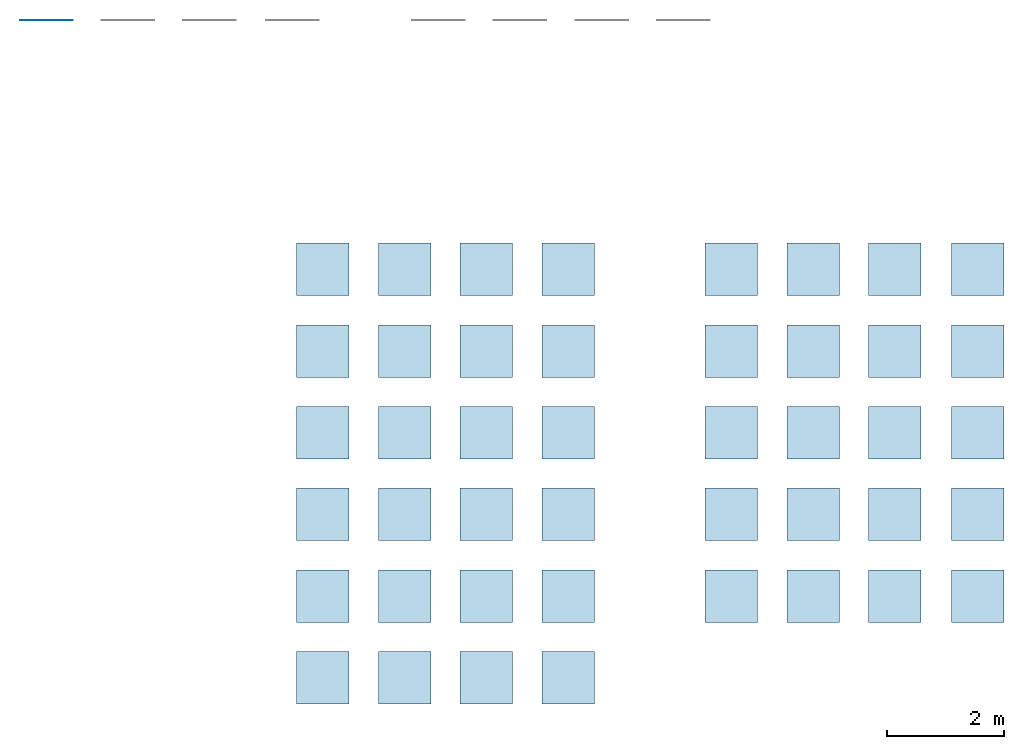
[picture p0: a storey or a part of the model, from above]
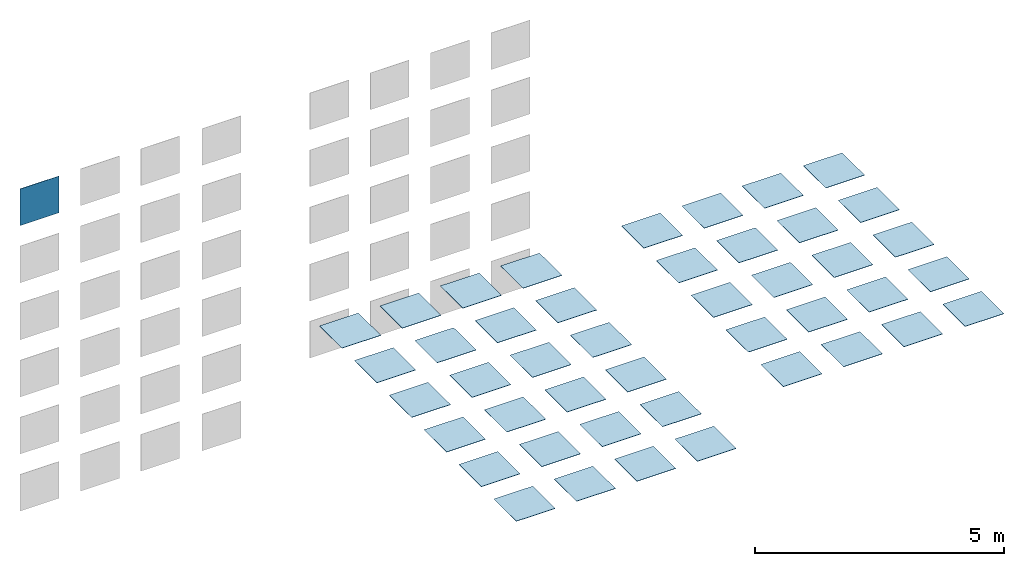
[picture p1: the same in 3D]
Properties of the parts of a building model (IFC2X3)

# File
Description: ViewDefinition [CoordinationView_V2.0]
File name: Número de proyecto
Time: 2017-10-19T10:44:05
Written by: The EXPRESS Data Manager Version 5.02.0100.07 : 28 Aug 2013
Made in: 20160225_1515(x64) - Exporter 17.0.416.0 - Alternate UI 17.12.14.0
Comment: STEP Physical File produced by: The EXPRESS Data Manager Version 5.02.0100.07 : 28 Aug 2013 * Module: EDMstepFileFactory/EDMstandAlone * Creation date: Thu Oct 19 10:44:05 2017 * Host: REVIT * Database: C:\Users\corte\AppData\Local\Temp\{5CBB84B9-D3AB-42C1-A525-BB3D4FEFA5DE}\ifc * Database version: 5507 * Database creation date: Thu Oct 19 10:44:02 2017 * Schema: IFC2X3 * Model: DataRepository.ifc * Model creation date: Thu Oct 19 10:44:02 2017 * Header model: DataRepository.ifc_HeaderModel * Header model creation date: Thu Oct 19 10:44:02 2017 * EDMuser: sdai-user * EDMgroup: sdai-group * License ID and type: 5605 : Permanent license. Expiry date: * EDMstepFileFactory options: 020000

# IfcProject, Número de proyecto
LongName: Nombre de proyecto; Phase: Estado de proyecto

# IfcSite, Default
RefLatitude: 40, 25, 0, 86975; RefLongitude: -3, -42, -1, -243858; RefElevation: 0 m

# IfcBuilding
Pset_BuildingCommon - NumberOfStoreys: 1

# IfcBuildingStorey, FARNESE FLOOR TILES
LongName: FARNESE FLOOR TILES; Elevation: 0 m

# IfcSlab: Suelo:VIVES AMALFI AZUL 30X30, Suelo:VIVES AMALFI AZUL 30X30:194230
In: FARNESE FLOOR TILES
PredefinedType: FLOOR; Material: VIVES AMALFI AZUL 30x30 0.0082 m
Pset_SlabCommon - IsExternal: no; LoadBearing: yes; PitchAngle: 0 deg; Reference: VIVES AMALFI AZUL 30X30; ThermalTransmittance: 182.927 kg/K/s3
Pset_ManufacturerTypeInformation - Manufacturer: VIVES Azulejos y Gres S.A.

# IfcSlab: Suelo:VIVES AMALFI BEIGE 30x30, Suelo:VIVES AMALFI BEIGE 30x30:194246
In: FARNESE FLOOR TILES
PredefinedType: FLOOR; Material: VIVES AMALFI BEIGE 30x30 0.0082 m
Pset_SlabCommon - IsExternal: no; LoadBearing: yes; PitchAngle: 0 deg; Reference: VIVES AMALFI BEIGE 30x30; ThermalTransmittance: 182.927 kg/K/s3
Pset_ManufacturerTypeInformation - Manufacturer: VIVES Azulejos y Gres S.A.

# IfcSlab: Suelo:VIVES AMALFI CEMENTO 30x30, Suelo:VIVES AMALFI CEMENTO 30x30:193908
In: FARNESE FLOOR TILES
PredefinedType: FLOOR; Material: VIVES AMALFI CEMENTO 30x30 0.0082 m
Pset_SlabCommon - IsExternal: no; LoadBearing: yes; PitchAngle: 0 deg; Reference: VIVES AMALFI CEMENTO 30x30; ThermalTransmittance: 182.927 kg/K/s3
Pset_ManufacturerTypeInformation - Manufacturer: VIVES Azulejos y Gres S.A.

# IfcSlab: Suelo:VIVES AMALFI CREMA 30x30, Suelo:VIVES AMALFI CREMA 30x30:193916
In: FARNESE FLOOR TILES
PredefinedType: FLOOR; Material: VIVES AMALFI CREMA 30x30 0.0082 m
Pset_SlabCommon - IsExternal: no; LoadBearing: yes; PitchAngle: 0 deg; Reference: VIVES AMALFI CREMA 30x30; ThermalTransmittance: 182.927 kg/K/s3
Pset_ManufacturerTypeInformation - Manufacturer: VIVES Azulejos y Gres S.A.

# IfcSlab: Suelo:VIVES AMALFI GRAFITO 30x30, Suelo:VIVES AMALFI GRAFITO 30x30:193924
In: FARNESE FLOOR TILES
PredefinedType: FLOOR; Material: VIVES AMALFI GRAFITO 30x30 0.0082 m
Pset_SlabCommon - IsExternal: no; LoadBearing: yes; PitchAngle: 0 deg; Reference: VIVES AMALFI GRAFITO 30x30; ThermalTransmittance: 182.927 kg/K/s3
Pset_ManufacturerTypeInformation - Manufacturer: VIVES Azulejos y Gres S.A.

# IfcSlab: Suelo:VIVES AMALFI HUMO 30X30, Suelo:VIVES AMALFI HUMO 30X30:193900
In: FARNESE FLOOR TILES
PredefinedType: FLOOR; Material: VIVES AMALFI HUMO 30x30 0.0082 m
Pset_SlabCommon - IsExternal: no; LoadBearing: yes; PitchAngle: 0 deg; Reference: VIVES AMALFI HUMO 30X30; ThermalTransmittance: 182.927 kg/K/s3
Pset_ManufacturerTypeInformation - Manufacturer: VIVES Azulejos y Gres S.A.

# IfcSlab: Suelo:VIVES AMALFI MAR 30x30, Suelo:VIVES AMALFI MAR 30x30:194238
In: FARNESE FLOOR TILES
PredefinedType: FLOOR; Material: VIVES AMALFI MAR 30x30 0.0082 m
Pset_SlabCommon - IsExternal: no; LoadBearing: yes; PitchAngle: 0 deg; Reference: VIVES AMALFI MAR 30x30; ThermalTransmittance: 182.927 kg/K/s3
Pset_ManufacturerTypeInformation - Manufacturer: VIVES Azulejos y Gres S.A.

# IfcSlab: Suelo:VIVES AMALFI ROSA 30x30, Suelo:VIVES AMALFI ROSA 30x30:194254
In: FARNESE FLOOR TILES
PredefinedType: FLOOR; Material: VIVES AMALFI ROSA 30x30 0.0082 m
Pset_SlabCommon - IsExternal: no; LoadBearing: yes; PitchAngle: 0 deg; Reference: VIVES AMALFI ROSA 30x30; ThermalTransmittance: 182.927 kg/K/s3
Pset_ManufacturerTypeInformation - Manufacturer: VIVES Azulejos y Gres S.A.

# IfcSlab: Suelo:VIVES AMALFI-R AZUL 29.3X29.3, Suelo:VIVES AMALFI-R AZUL 29.3X29.3:196299
In: FARNESE FLOOR TILES
PredefinedType: FLOOR; Material: VIVES AMALFI-R AZUL 29.3x29.3 0.0082 m
Pset_SlabCommon - IsExternal: no; LoadBearing: yes; PitchAngle: 0 deg; Reference: VIVES AMALFI-R AZUL 29.3X29.3; ThermalTransmittance: 182.927 kg/K/s3
Pset_ManufacturerTypeInformation - Manufacturer: VIVES Azulejos y Gres S.A.

# IfcSlab: Suelo:VIVES AMALFI-R BEIGE 29.3X29.3 2, Suelo:VIVES AMALFI-R BEIGE 29.3X29.3 2:196315
In: FARNESE FLOOR TILES
PredefinedType: FLOOR; Material: VIVES AMALFI-R BEIGE 29.3x29.3 0.0082 m
Pset_SlabCommon - IsExternal: no; LoadBearing: yes; PitchAngle: 0 deg; Reference: VIVES AMALFI-R BEIGE 29.3X29.3 2; ThermalTransmittance: 182.927 kg/K/s3
Pset_ManufacturerTypeInformation - Manufacturer: VIVES Azulejos y Gres S.A.

# IfcSlab: Suelo:VIVES AMALFI-R CEMENTO 29.3X29.3, Suelo:VIVES AMALFI-R CEMENTO 29.3X29.3:196037
In: FARNESE FLOOR TILES
PredefinedType: FLOOR; Material: VIVES AMALFI-R CEMENTO 29.3x29.3 0.0082 m
Pset_SlabCommon - IsExternal: no; LoadBearing: yes; PitchAngle: 0 deg; Reference: VIVES AMALFI-R CEMENTO 29.3X29.3; ThermalTransmittance: 182.927 kg/K/s3
Pset_ManufacturerTypeInformation - Manufacturer: VIVES Azulejos y Gres S.A.

# IfcSlab: Suelo:VIVES AMALFI-R CREMA 29.3X29.3, Suelo:VIVES AMALFI-R CREMA 29.3X29.3:196045
In: FARNESE FLOOR TILES
PredefinedType: FLOOR; Material: VIVES AMALFI-R CREMA 29.3x29.3 0.0082 m
Pset_SlabCommon - IsExternal: no; LoadBearing: yes; PitchAngle: 0 deg; Reference: VIVES AMALFI-R CREMA 29.3X29.3; ThermalTransmittance: 182.927 kg/K/s3
Pset_ManufacturerTypeInformation - Manufacturer: VIVES Azulejos y Gres S.A.

# IfcSlab: Suelo:VIVES AMALFI-R GRAFITO 29.3X29.3, Suelo:VIVES AMALFI-R GRAFITO 29.3X29.3:196053
In: FARNESE FLOOR TILES
PredefinedType: FLOOR; Material: VIVES AMALFI-R GRAFITO 29.3x29.3 0.0082 m
Pset_SlabCommon - IsExternal: no; LoadBearing: yes; PitchAngle: 0 deg; Reference: VIVES AMALFI-R GRAFITO 29.3X29.3; ThermalTransmittance: 182.927 kg/K/s3
Pset_ManufacturerTypeInformation - Manufacturer: VIVES Azulejos y Gres S.A.

# IfcSlab: Suelo:VIVES AMALFI-R HUMO 29.3X29.3, Suelo:VIVES AMALFI-R HUMO 29.3X29.3:196029
In: FARNESE FLOOR TILES
PredefinedType: FLOOR; Material: VIVES AMALFI-R HUMO 29.3x29.3 0.0082 m
Pset_SlabCommon - IsExternal: no; LoadBearing: yes; PitchAngle: 0 deg; Reference: VIVES AMALFI-R HUMO 29.3X29.3; ThermalTransmittance: 182.927 kg/K/s3
Pset_ManufacturerTypeInformation - Manufacturer: VIVES Azulejos y Gres S.A.

# IfcSlab: Suelo:VIVES AMALFI-R MAR 29.3X29.3, Suelo:VIVES AMALFI-R MAR 29.3X29.3:196307
In: FARNESE FLOOR TILES
PredefinedType: FLOOR; Material: VIVES AMALFI-R MAR 29.3x29.3 0.0082 m
Pset_SlabCommon - IsExternal: no; LoadBearing: yes; PitchAngle: 0 deg; Reference: VIVES AMALFI-R MAR 29.3X29.3; ThermalTransmittance: 182.927 kg/K/s3
Pset_ManufacturerTypeInformation - Manufacturer: VIVES Azulejos y Gres S.A.

# IfcSlab: Suelo:VIVES AMALFI-R ROSA 29.3X29.3, Suelo:VIVES AMALFI-R ROSA 29.3X29.3:196323
In: FARNESE FLOOR TILES
PredefinedType: FLOOR; Material: VIVES AMALFI-R ROSA 29.3x29.3 0.0082 m
Pset_SlabCommon - IsExternal: no; LoadBearing: yes; PitchAngle: 0 deg; Reference: VIVES AMALFI-R ROSA 29.3X29.3; ThermalTransmittance: 182.927 kg/K/s3
Pset_ManufacturerTypeInformation - Manufacturer: VIVES Azulejos y Gres S.A.

# IfcSlab: Suelo:VIVES APULIA-R CREMA 29.3X29.3, Suelo:VIVES APULIA-R CREMA 29.3X29.3:196544
In: FARNESE FLOOR TILES
PredefinedType: FLOOR; Material: VIVES APULIA-R CREMA 29.3x29.3 0.0082 m
Pset_SlabCommon - IsExternal: no; LoadBearing: yes; PitchAngle: 0 deg; Reference: VIVES APULIA-R CREMA 29.3X29.3; ThermalTransmittance: 182.927 kg/K/s3
Pset_ManufacturerTypeInformation - Manufacturer: VIVES Azulejos y Gres S.A.

# IfcSlab: Suelo:VIVES APULIA-R HUMO 29.3X29.3, Suelo:VIVES APULIA-R HUMO 29.3X29.3:196552
In: FARNESE FLOOR TILES
PredefinedType: FLOOR; Material: VIVES APULIA-R HUMO 29.3x29.3 0.0082 m
Pset_SlabCommon - IsExternal: no; LoadBearing: yes; PitchAngle: 0 deg; Reference: VIVES APULIA-R HUMO 29.3X29.3; ThermalTransmittance: 182.927 kg/K/s3
Pset_ManufacturerTypeInformation - Manufacturer: VIVES Azulejos y Gres S.A.

# IfcSlab: Suelo:VIVES APULIA-R MULTICOLOR 29.3X29.3, Suelo:VIVES APULIA-R MULTICOLOR 29.3X29.3:196536
In: FARNESE FLOOR TILES
PredefinedType: FLOOR; Material: VIVES APULIA-R MULTICOLOR 29.3x29.3 0.0082 m
Pset_SlabCommon - IsExternal: no; LoadBearing: yes; PitchAngle: 0 deg; Reference: VIVES APULIA-R MULTICOLOR 29.3X29.3; ThermalTransmittance: 182.927 kg/K/s3
Pset_ManufacturerTypeInformation - Manufacturer: VIVES Azulejos y Gres S.A.

# IfcSlab: Suelo:VIVES AVENTINO-R CREMA 29.3X29.3, Suelo:VIVES AVENTINO-R CREMA 29.3X29.3:196757
In: FARNESE FLOOR TILES
PredefinedType: FLOOR; Material: VIVES AVENTINO-R CREMA 29.3x29.3 0.0082 m
Pset_SlabCommon - IsExternal: no; LoadBearing: yes; PitchAngle: 0 deg; Reference: VIVES AVENTINO-R CREMA 29.3X29.3; ThermalTransmittance: 182.927 kg/K/s3
Pset_ManufacturerTypeInformation - Manufacturer: VIVES Azulejos y Gres S.A.

# IfcSlab: Suelo:VIVES AVENTINO-R HUMO 29.3X29.3, Suelo:VIVES AVENTINO-R HUMO 29.3X29.3:196765
In: FARNESE FLOOR TILES
PredefinedType: FLOOR; Material: VIVES AVENTINO-R HUMO 29.3x29.3 0.0082 m
Pset_SlabCommon - IsExternal: no; LoadBearing: yes; PitchAngle: 0 deg; Reference: VIVES AVENTINO-R HUMO 29.3X29.3; ThermalTransmittance: 182.927 kg/K/s3
Pset_ManufacturerTypeInformation - Manufacturer: VIVES Azulejos y Gres S.A.

# IfcSlab: Suelo:VIVES CAVOUR AZUL 30x30, Suelo:VIVES CAVOUR AZUL 30x30:195039
In: FARNESE FLOOR TILES
PredefinedType: FLOOR; Material: VIVES CAVOUR AZUL 30x30 0.0082 m
Pset_SlabCommon - IsExternal: no; LoadBearing: yes; PitchAngle: 0 deg; Reference: VIVES CAVOUR AZUL 30x30; ThermalTransmittance: 182.927 kg/K/s3
Pset_ManufacturerTypeInformation - Manufacturer: VIVES Azulejos y Gres S.A.

# IfcSlab: Suelo:VIVES CAVOUR CEMENTO 30x30, Suelo:VIVES CAVOUR CEMENTO 30x30:195031
In: FARNESE FLOOR TILES
PredefinedType: FLOOR; Material: VIVES CAVOUR CEMENTO 30x30 0.0082 m
Pset_SlabCommon - IsExternal: no; LoadBearing: yes; PitchAngle: 0 deg; Reference: VIVES CAVOUR CEMENTO 30x30; ThermalTransmittance: 182.927 kg/K/s3
Pset_ManufacturerTypeInformation - Manufacturer: VIVES Azulejos y Gres S.A.

# IfcSlab: Suelo:VIVES FARNESE CEMENTO 30x30, Suelo:VIVES FARNESE CEMENTO 30x30:193648
In: FARNESE FLOOR TILES
PredefinedType: FLOOR; Material: VIVES FARNESE CEMENTO 30x30 0.0082 m
Pset_SlabCommon - IsExternal: no; LoadBearing: yes; PitchAngle: 0 deg; Reference: VIVES FARNESE CEMENTO 30x30; ThermalTransmittance: 182.927 kg/K/s3
Pset_ManufacturerTypeInformation - Manufacturer: VIVES Azulejos y Gres S.A.

# IfcSlab: Suelo:VIVES FARNESE CREMA 30x30 2, Suelo:VIVES FARNESE CREMA 30x30 2:193729
In: FARNESE FLOOR TILES
PredefinedType: FLOOR; Material: VIVES FARNESE CREMA 30x30 0.0082 m
Pset_SlabCommon - IsExternal: no; LoadBearing: yes; PitchAngle: 0 deg; Reference: VIVES FARNESE CREMA 30x30 2; ThermalTransmittance: 182.927 kg/K/s3
Pset_ManufacturerTypeInformation - Manufacturer: VIVES Azulejos y Gres S.A.

# IfcSlab: Suelo:VIVES FARNESE GRAFITO 30x30, Suelo:VIVES FARNESE GRAFITO 30x30:193795
In: FARNESE FLOOR TILES
PredefinedType: FLOOR; Material: VIVES FARNESE GRAFITO 30x30 0.0082 m
Pset_SlabCommon - IsExternal: no; LoadBearing: yes; PitchAngle: 0 deg; Reference: VIVES FARNESE GRAFITO 30x30; ThermalTransmittance: 182.927 kg/K/s3
Pset_ManufacturerTypeInformation - Manufacturer: VIVES Azulejos y Gres S.A.

# IfcSlab: Suelo:VIVES FARNESE HUMO 30x30, Suelo:VIVES FARNESE HUMO 30x30:189750
In: FARNESE FLOOR TILES
PredefinedType: FLOOR; Material: VIVES FARNESE HUMO 30x30 0.0082 m
Pset_SlabCommon - Reference: VIVES FARNESE HUMO 30x30; IsExternal: no; LoadBearing: yes; ThermalTransmittance: 182.927 kg/K/s3; PitchAngle: 0 deg
Pset_ManufacturerTypeInformation - Manufacturer: VIVES Azulejos y Gres S.A.

# IfcSlab: Suelo:VIVES FARNESE-R CEMENTO 29.3X29.3, Suelo:VIVES FARNESE-R CEMENTO 29.3X29.3:195831
In: FARNESE FLOOR TILES
PredefinedType: FLOOR; Material: VIVES FARNESE-R CEMENTO 29.3x29.3 0.0082 m
Pset_SlabCommon - IsExternal: no; LoadBearing: yes; PitchAngle: 0 deg; Reference: VIVES FARNESE-R CEMENTO 29.3X29.3; ThermalTransmittance: 182.927 kg/K/s3
Pset_ManufacturerTypeInformation - Manufacturer: VIVES Azulejos y Gres S.A.

# IfcSlab: Suelo:VIVES FARNESE-R CREMA 29.3X29.3, Suelo:VIVES FARNESE-R CREMA 29.3X29.3:195897
In: FARNESE FLOOR TILES
PredefinedType: FLOOR; Material: VIVES FARNESE-R CREMA 29.3x29.3 0.0082 m
Pset_SlabCommon - IsExternal: no; LoadBearing: yes; PitchAngle: 0 deg; Reference: VIVES FARNESE-R CREMA 29.3X29.3; ThermalTransmittance: 182.927 kg/K/s3
Pset_ManufacturerTypeInformation - Manufacturer: VIVES Azulejos y Gres S.A.

# IfcSlab: Suelo:VIVES FARNESE-R GRAFITO 29.3X29.3, Suelo:VIVES FARNESE-R GRAFITO 29.3X29.3:195961
In: FARNESE FLOOR TILES
PredefinedType: FLOOR; Material: VIVES FARNESE-R GRAFITO 29.3x29.3 0.0082 m
Pset_SlabCommon - IsExternal: no; LoadBearing: yes; PitchAngle: 0 deg; Reference: VIVES FARNESE-R GRAFITO 29.3X29.3; ThermalTransmittance: 182.927 kg/K/s3
Pset_ManufacturerTypeInformation - Manufacturer: VIVES Azulejos y Gres S.A.

# IfcSlab: Suelo:VIVES FARNESE-R HUMO 29.3X29.3, Suelo:VIVES FARNESE-R HUMO 29.3X29.3:195707
In: FARNESE FLOOR TILES
PredefinedType: FLOOR; Material: VIVES FARNESE-R HUMO 29.3x29.3 0.0082 m
Pset_SlabCommon - IsExternal: no; LoadBearing: yes; PitchAngle: 0 deg; Reference: VIVES FARNESE-R HUMO 29.3X29.3; ThermalTransmittance: 182.927 kg/K/s3
Pset_ManufacturerTypeInformation - Manufacturer: VIVES Azulejos y Gres S.A.

# IfcSlab: Suelo:VIVES GADNER CEMENTO 30x30, Suelo:VIVES GADNER CEMENTO 30x30:195055
In: FARNESE FLOOR TILES
PredefinedType: FLOOR; Material: VIVES GADNER CEMENTO 30x30 0.0082 m
Pset_SlabCommon - IsExternal: no; LoadBearing: yes; PitchAngle: 0 deg; Reference: VIVES GADNER CEMENTO 30x30; ThermalTransmittance: 182.927 kg/K/s3
Pset_ManufacturerTypeInformation - Manufacturer: VIVES Azulejos y Gres S.A.

# IfcSlab: Suelo:VIVES GADNER CREMA 30x30, Suelo:VIVES GADNER CREMA 30x30:195047
In: FARNESE FLOOR TILES
PredefinedType: FLOOR; Material: VIVES GADNER CREMA 30x30 0.0082 m
Pset_SlabCommon - IsExternal: no; LoadBearing: yes; PitchAngle: 0 deg; Reference: VIVES GADNER CREMA 30x30; ThermalTransmittance: 182.927 kg/K/s3
Pset_ManufacturerTypeInformation - Manufacturer: VIVES Azulejos y Gres S.A.

# IfcSlab: Suelo:VIVES MANCINI AZUL 30X30, Suelo:VIVES MANCINI AZUL 30X30:194849
In: FARNESE FLOOR TILES
PredefinedType: FLOOR; Material: VIVES MANCINI AZUL 30x30 0.0082 m
Pset_SlabCommon - IsExternal: no; LoadBearing: yes; PitchAngle: 0 deg; Reference: VIVES MANCINI AZUL 30X30; ThermalTransmittance: 182.927 kg/K/s3
Pset_ManufacturerTypeInformation - Manufacturer: VIVES Azulejos y Gres S.A.

# IfcSlab: Suelo:VIVES MANCINI BEIGE 30x30, Suelo:VIVES MANCINI BEIGE 30x30:194865
In: FARNESE FLOOR TILES
PredefinedType: FLOOR; Material: VIVES MANCINI BEIGE 30x30 0.0082 m
Pset_SlabCommon - IsExternal: no; LoadBearing: yes; PitchAngle: 0 deg; Reference: VIVES MANCINI BEIGE 30x30; ThermalTransmittance: 182.927 kg/K/s3
Pset_ManufacturerTypeInformation - Manufacturer: VIVES Azulejos y Gres S.A.

# IfcSlab: Suelo:VIVES MANCINI CEMENTO 30x30, Suelo:VIVES MANCINI CEMENTO 30x30:194641
In: FARNESE FLOOR TILES
PredefinedType: FLOOR; Material: VIVES MANCINI CEMENTO 30x30 0.0082 m
Pset_SlabCommon - IsExternal: no; LoadBearing: yes; PitchAngle: 0 deg; Reference: VIVES MANCINI CEMENTO 30x30; ThermalTransmittance: 182.927 kg/K/s3
Pset_ManufacturerTypeInformation - Manufacturer: VIVES Azulejos y Gres S.A.

# IfcSlab: Suelo:VIVES MANCINI CREMA 30x30, Suelo:VIVES MANCINI CREMA 30x30:194649
In: FARNESE FLOOR TILES
PredefinedType: FLOOR; Material: VIVES MANCINI CREMA 30x30 0.0082 m
Pset_SlabCommon - IsExternal: no; LoadBearing: yes; PitchAngle: 0 deg; Reference: VIVES MANCINI CREMA 30x30; ThermalTransmittance: 182.927 kg/K/s3
Pset_ManufacturerTypeInformation - Manufacturer: VIVES Azulejos y Gres S.A.

# IfcSlab: Suelo:VIVES MANCINI GRAFITO 30x30 (2)
In: FARNESE FLOOR TILES
PredefinedType: FLOOR; Material: VIVES AMALFI ROSA 30x30 0.0082 m
Pset_SlabCommon - IsExternal: no; LoadBearing: yes; PitchAngle: 0 deg; Reference: VIVES MANCINI GRAFITO 30x30; ThermalTransmittance: 182.927 kg/K/s3
Pset_ManufacturerTypeInformation - Manufacturer: VIVES Azulejos y Gres S.A.
Name (Suelo:VIVES MANCINI GRAFITO 30x30:...)
194657
194873

# IfcSlab: Suelo:VIVES MANCINI HUMO 30X30, Suelo:VIVES MANCINI HUMO 30X30:194633
In: FARNESE FLOOR TILES
PredefinedType: FLOOR; Material: VIVES MANCINI HUMO 30x30 0.0082 m
Pset_SlabCommon - IsExternal: no; LoadBearing: yes; PitchAngle: 0 deg; Reference: VIVES MANCINI HUMO 30X30; ThermalTransmittance: 182.927 kg/K/s3
Pset_ManufacturerTypeInformation - Manufacturer: VIVES Azulejos y Gres S.A.

# IfcSlab: Suelo:VIVES MANCINI MAR 30x30, Suelo:VIVES MANCINI MAR 30x30:194857
In: FARNESE FLOOR TILES
PredefinedType: FLOOR; Material: VIVES MANCINI MAR 30x30 0.0082 m
Pset_SlabCommon - IsExternal: no; LoadBearing: yes; PitchAngle: 0 deg; Reference: VIVES MANCINI MAR 30x30; ThermalTransmittance: 182.927 kg/K/s3
Pset_ManufacturerTypeInformation - Manufacturer: VIVES Azulejos y Gres S.A.

# IfcSlab: Suelo:VIVES MOLISE-R CREMA 29.3X29.3, Suelo:VIVES MOLISE-R CREMA 29.3X29.3:196773
In: FARNESE FLOOR TILES
PredefinedType: FLOOR; Material: VIVES MOLISE-R CREMA 29.3x29.3 0.0082 m
Pset_SlabCommon - IsExternal: no; LoadBearing: yes; PitchAngle: 0 deg; Reference: VIVES MOLISE-R CREMA 29.3X29.3; ThermalTransmittance: 182.927 kg/K/s3
Pset_ManufacturerTypeInformation - Manufacturer: VIVES Azulejos y Gres S.A.

# IfcSlab: Suelo:VIVES MOLISE-R GRAFITO 29.3X29.3, Suelo:VIVES MOLISE-R GRAFITO 29.3X29.3:196781
In: FARNESE FLOOR TILES
PredefinedType: FLOOR; Material: VIVES MOLISE-R GRAFITO 29.3x29.3 0.0082 m
Pset_SlabCommon - IsExternal: no; LoadBearing: yes; PitchAngle: 0 deg; Reference: VIVES MOLISE-R GRAFITO 29.3X29.3; ThermalTransmittance: 182.927 kg/K/s3
Pset_ManufacturerTypeInformation - Manufacturer: VIVES Azulejos y Gres S.A.

# IfcSlab: Suelo:VIVES QUIRINALE-R MULTICOLOR 29.3X29.3, Suelo:VIVES QUIRINALE-R MULTICOLOR 29.3X29.3:196528
In: FARNESE FLOOR TILES
PredefinedType: FLOOR; Material: VIVES QUIRINALE-R MULTICOLOR 29.3x29.3 0.0082 m
Pset_SlabCommon - IsExternal: no; LoadBearing: yes; PitchAngle: 0 deg; Reference: VIVES QUIRINALE-R MULTICOLOR 29.3X29.3; ThermalTransmittance: 182.927 kg/K/s3
Pset_ManufacturerTypeInformation - Manufacturer: VIVES Azulejos y Gres S.A.

# IfcWallStandardCase: Muro básico:CAVOUR AZUL 30x30, Muro básico:CAVOUR AZUL 30x30:201446
In: FARNESE FLOOR TILES
Type - PredefinedType: STANDARD; Material: VIVES CAVOUR AZUL 30x30 0.0082 m
Pset_WallCommon - IsExternal: no; LoadBearing: no; ExtendToStructure: no; Reference: CAVOUR AZUL 30x30; ThermalTransmittance: 182.927 kg/K/s3
Pset_ManufacturerTypeInformation - Manufacturer: VIVES Azulejos y Gres S.A.

# IfcWallStandardCase: Muro básico:MANCINI CEMENTO 30x30, Muro básico:MANCINI CEMENTO 30x30:199084
In: FARNESE FLOOR TILES
Type - PredefinedType: STANDARD; Material: VIVES MANCINI CEMENTO 30x30 0.0082 m
Pset_WallCommon - IsExternal: no; LoadBearing: no; ExtendToStructure: no; Reference: MANCINI CEMENTO 30x30; ThermalTransmittance: 182.927 kg/K/s3
Pset_ManufacturerTypeInformation - Manufacturer: VIVES Azulejos y Gres S.A.

# IfcWallStandardCase: Muro básico:MANCINI MAR 30x30, Muro básico:MANCINI MAR 30x30:200587
In: FARNESE FLOOR TILES
Type - PredefinedType: STANDARD; Material: VIVES MANCINI MAR 30x30 0.0082 m
Pset_WallCommon - IsExternal: no; LoadBearing: no; ExtendToStructure: no; Reference: MANCINI MAR 30x30; ThermalTransmittance: 182.927 kg/K/s3
Pset_ManufacturerTypeInformation - Manufacturer: VIVES Azulejos y Gres S.A.

# IfcWallStandardCase: Muro básico:VIVES AMALFI AZUL30x30, Muro básico:VIVES AMALFI AZUL30x30:198633
In: FARNESE FLOOR TILES
Type - PredefinedType: STANDARD; Material: VIVES AMALFI AZUL 30x30 0.0082 m
Pset_WallCommon - IsExternal: no; LoadBearing: no; ExtendToStructure: no; Reference: VIVES AMALFI AZUL30x30; ThermalTransmittance: 182.927 kg/K/s3
Pset_ManufacturerTypeInformation - Manufacturer: VIVES Azulejos y Gres S.A.

# IfcWallStandardCase: Muro básico:VIVES AMALFI BEIGE 30x30, Muro básico:VIVES AMALFI BEIGE 30x30:198665
In: FARNESE FLOOR TILES
Type - PredefinedType: STANDARD; Material: VIVES AMALFI BEIGE 30x30 0.0082 m
Pset_WallCommon - IsExternal: no; LoadBearing: no; ExtendToStructure: no; Reference: VIVES AMALFI BEIGE 30x30; ThermalTransmittance: 182.927 kg/K/s3
Pset_ManufacturerTypeInformation - Manufacturer: VIVES Azulejos y Gres S.A.

# IfcWallStandardCase: Muro básico:VIVES AMALFI CEMENTO 30x30, Muro básico:VIVES AMALFI CEMENTO 30x30:198119
In: FARNESE FLOOR TILES
Type - PredefinedType: STANDARD; Material: VIVES AMALFI CEMENTO 30x30 0.0082 m
Pset_WallCommon - IsExternal: no; LoadBearing: no; ExtendToStructure: no; Reference: VIVES AMALFI CEMENTO 30x30; ThermalTransmittance: 182.927 kg/K/s3
Pset_ManufacturerTypeInformation - Manufacturer: VIVES Azulejos y Gres S.A.

# IfcWallStandardCase: Muro básico:VIVES AMALFI CREMA 30x30, Muro básico:VIVES AMALFI CREMA 30x30:198135
In: FARNESE FLOOR TILES
Type - PredefinedType: STANDARD; Material: VIVES AMALFI CREMA 30x30 0.0082 m
Pset_WallCommon - IsExternal: no; LoadBearing: no; ExtendToStructure: no; Reference: VIVES AMALFI CREMA 30x30; ThermalTransmittance: 182.927 kg/K/s3
Pset_ManufacturerTypeInformation - Manufacturer: VIVES Azulejos y Gres S.A.

# IfcWallStandardCase: Muro básico:VIVES AMALFI GRAFITO 30x30, Muro básico:VIVES AMALFI GRAFITO 30x30:198151
In: FARNESE FLOOR TILES
Type - PredefinedType: STANDARD; Material: VIVES AMALFI GRAFITO 30x30 0.0082 m
Pset_WallCommon - IsExternal: no; LoadBearing: no; ExtendToStructure: no; Reference: VIVES AMALFI GRAFITO 30x30; ThermalTransmittance: 182.927 kg/K/s3
Pset_ManufacturerTypeInformation - Manufacturer: VIVES Azulejos y Gres S.A.

# IfcWallStandardCase: Muro básico:VIVES AMALFI HUMO 30x30, Muro básico:VIVES AMALFI HUMO 30x30:198103
In: FARNESE FLOOR TILES
Type - PredefinedType: STANDARD; Material: VIVES AMALFI HUMO 30x30 0.0082 m
Pset_WallCommon - IsExternal: no; LoadBearing: no; ExtendToStructure: no; Reference: VIVES AMALFI HUMO 30x30; ThermalTransmittance: 182.927 kg/K/s3
Pset_ManufacturerTypeInformation - Manufacturer: VIVES Azulejos y Gres S.A.

# IfcWallStandardCase: Muro básico:VIVES AMALFI MAR 30x30, Muro básico:VIVES AMALFI MAR 30x30:198649
In: FARNESE FLOOR TILES
Type - PredefinedType: STANDARD; Material: VIVES AMALFI MAR 30x30 0.0082 m
Pset_WallCommon - IsExternal: no; LoadBearing: no; ExtendToStructure: no; Reference: VIVES AMALFI MAR 30x30; ThermalTransmittance: 182.927 kg/K/s3
Pset_ManufacturerTypeInformation - Manufacturer: VIVES Azulejos y Gres S.A.

# IfcWallStandardCase: Muro básico:VIVES AMALFI ROSA 30x30, Muro básico:VIVES AMALFI ROSA 30x30:198681
In: FARNESE FLOOR TILES
Type - PredefinedType: STANDARD; Material: VIVES AMALFI ROSA 30x30 0.0082 m
Pset_WallCommon - IsExternal: no; LoadBearing: no; ExtendToStructure: no; Reference: VIVES AMALFI ROSA 30x30; ThermalTransmittance: 182.927 kg/K/s3
Pset_ManufacturerTypeInformation - Manufacturer: VIVES Azulejos y Gres S.A.

# IfcWallStandardCase: Muro básico:VIVES AMALFI-R AZUL 29.3X29.3, Muro básico:VIVES AMALFI-R AZUL 29.3X29.3:203031
In: FARNESE FLOOR TILES
Type - PredefinedType: STANDARD; Material: VIVES AMALFI-R AZUL 29.3x29.3 0.0082 m
Pset_WallCommon - IsExternal: no; LoadBearing: no; ExtendToStructure: no; Reference: VIVES AMALFI-R AZUL 29.3X29.3; ThermalTransmittance: 182.927 kg/K/s3
Pset_ManufacturerTypeInformation - Manufacturer: VIVES Azulejos y Gres S.A.

# IfcWallStandardCase: Muro básico:VIVES AMALFI-R BEIGE 29.3X29.3 2, Muro básico:VIVES AMALFI-R BEIGE 29.3X29.3 2:203063
In: FARNESE FLOOR TILES
Type - PredefinedType: STANDARD; Material: VIVES AMALFI-R BEIGE 29.3x29.3 0.0082 m
Pset_WallCommon - IsExternal: no; LoadBearing: no; ExtendToStructure: no; Reference: VIVES AMALFI-R BEIGE 29.3X29.3 2; ThermalTransmittance: 182.927 kg/K/s3
Pset_ManufacturerTypeInformation - Manufacturer: VIVES Azulejos y Gres S.A.

# IfcWallStandardCase: Muro básico:VIVES AMALFI-R CEMENTO 29.3X29.3, Muro básico:VIVES AMALFI-R CEMENTO 29.3X29.3:202626
In: FARNESE FLOOR TILES
Type - PredefinedType: STANDARD; Material: VIVES FARNESE-R CEMENTO 29.3x29.3 0.0082 m
Pset_WallCommon - IsExternal: no; LoadBearing: no; ExtendToStructure: no; Reference: VIVES AMALFI-R CEMENTO 29.3X29.3; ThermalTransmittance: 182.927 kg/K/s3
Pset_ManufacturerTypeInformation - Manufacturer: VIVES Azulejos y Gres S.A.

# IfcWallStandardCase: Muro básico:VIVES AMALFI-R CREMA 29.3X29.3, Muro básico:VIVES AMALFI-R CREMA 29.3X29.3:202642
In: FARNESE FLOOR TILES
Type - PredefinedType: STANDARD; Material: VIVES AMALFI-R CREMA 29.3x29.3 0.0082 m
Pset_WallCommon - IsExternal: no; LoadBearing: no; ExtendToStructure: no; Reference: VIVES AMALFI-R CREMA 29.3X29.3; ThermalTransmittance: 182.927 kg/K/s3
Pset_ManufacturerTypeInformation - Manufacturer: VIVES Azulejos y Gres S.A.

# IfcWallStandardCase: Muro básico:VIVES AMALFI-R GRAFITO 29.3X29.3, Muro básico:VIVES AMALFI-R GRAFITO 29.3X29.3:202658
In: FARNESE FLOOR TILES
Type - PredefinedType: STANDARD; Material: VIVES AMALFI-R GRAFITO 29.3x29.3 0.0082 m
Pset_WallCommon - IsExternal: no; LoadBearing: no; ExtendToStructure: no; Reference: VIVES AMALFI-R GRAFITO 29.3X29.3; ThermalTransmittance: 182.927 kg/K/s3
Pset_ManufacturerTypeInformation - Manufacturer: VIVES Azulejos y Gres S.A.

# IfcWallStandardCase: Muro básico:VIVES AMALFI-R HUMO 29.3X29.3, Muro básico:VIVES AMALFI-R HUMO 29.3X29.3:202610
In: FARNESE FLOOR TILES
Type - PredefinedType: STANDARD; Material: VIVES AMALFI-R HUMO 29.3x29.3 0.0082 m
Pset_WallCommon - IsExternal: no; LoadBearing: no; ExtendToStructure: no; Reference: VIVES AMALFI-R HUMO 29.3X29.3; ThermalTransmittance: 182.927 kg/K/s3
Pset_ManufacturerTypeInformation - Manufacturer: VIVES Azulejos y Gres S.A.

# IfcWallStandardCase: Muro básico:VIVES AMALFI-R MAR 29.3X29.3, Muro básico:VIVES AMALFI-R MAR 29.3X29.3:203047
In: FARNESE FLOOR TILES
Type - PredefinedType: STANDARD; Material: VIVES AMALFI-R MAR 29.3x29.3 0.0082 m
Pset_WallCommon - IsExternal: no; LoadBearing: no; ExtendToStructure: no; Reference: VIVES AMALFI-R MAR 29.3X29.3; ThermalTransmittance: 182.927 kg/K/s3
Pset_ManufacturerTypeInformation - Manufacturer: VIVES Azulejos y Gres S.A.

# IfcWallStandardCase: Muro básico:VIVES AMALFI-R ROSA 29.3X29.3, Muro básico:VIVES AMALFI-R ROSA 29.3X29.3:203079
In: FARNESE FLOOR TILES
Type - PredefinedType: STANDARD; Material: VIVES AMALFI-R ROSA 29.3x29.3 0.0082 m
Pset_WallCommon - IsExternal: no; LoadBearing: no; ExtendToStructure: no; Reference: VIVES AMALFI-R ROSA 29.3X29.3; ThermalTransmittance: 182.927 kg/K/s3
Pset_ManufacturerTypeInformation - Manufacturer: VIVES Azulejos y Gres S.A.

# IfcWallStandardCase: Muro básico:VIVES APULIA-R CREMA 29.3X29.3, Muro básico:VIVES APULIA-R CREMA 29.3X29.3:203451
In: FARNESE FLOOR TILES
Type - PredefinedType: STANDARD; Material: VIVES APULIA-R CREMA 29.3x29.3 0.0082 m
Pset_WallCommon - IsExternal: no; LoadBearing: no; ExtendToStructure: no; Reference: VIVES APULIA-R CREMA 29.3X29.3; ThermalTransmittance: 182.927 kg/K/s3
Pset_ManufacturerTypeInformation - Manufacturer: VIVES Azulejos y Gres S.A.

# IfcWallStandardCase: Muro básico:VIVES APULIA-R HUMO 29.3X29.3, Muro básico:VIVES APULIA-R HUMO 29.3X29.3:203467
In: FARNESE FLOOR TILES
Type - PredefinedType: STANDARD; Material: VIVES APULIA-R HUMO 29.3x29.3 0.0082 m
Pset_WallCommon - IsExternal: no; LoadBearing: no; ExtendToStructure: no; Reference: VIVES APULIA-R HUMO 29.3X29.3; ThermalTransmittance: 182.927 kg/K/s3
Pset_ManufacturerTypeInformation - Manufacturer: VIVES Azulejos y Gres S.A.

# IfcWallStandardCase: Muro básico:VIVES APULIA-R MULTICOLOR 29.3X29.3, Muro básico:VIVES APULIA-R MULTICOLOR 29.3X29.3:203435
In: FARNESE FLOOR TILES
Type - PredefinedType: STANDARD; Material: VIVES APULIA-R MULTICOLOR 29.3x29.3 0.0082 m
Pset_WallCommon - IsExternal: no; LoadBearing: no; ExtendToStructure: no; Reference: VIVES APULIA-R MULTICOLOR 29.3X29.3; ThermalTransmittance: 182.927 kg/K/s3
Pset_ManufacturerTypeInformation - Manufacturer: VIVES Azulejos y Gres S.A.

# IfcWallStandardCase: Muro básico:VIVES AVENTINO-R CREMA 29.3X29.3, Muro básico:VIVES AVENTINO-R CREMA 29.3X29.3:203782
In: FARNESE FLOOR TILES
Type - PredefinedType: STANDARD; Material: VIVES AVENTINO-R CREMA 29.3x29.3 0.0082 m
Pset_WallCommon - IsExternal: no; LoadBearing: no; ExtendToStructure: no; Reference: VIVES AVENTINO-R CREMA 29.3X29.3; ThermalTransmittance: 182.927 kg/K/s3
Pset_ManufacturerTypeInformation - Manufacturer: VIVES Azulejos y Gres S.A.

# IfcWallStandardCase: Muro básico:VIVES AVENTINO-R HUMO 29.3X29.3, Muro básico:VIVES AVENTINO-R HUMO 29.3X29.3:203798
In: FARNESE FLOOR TILES
Type - PredefinedType: STANDARD; Material: VIVES AVENTINO-R HUMO 29.3x29.3 0.0082 m
Pset_WallCommon - IsExternal: no; LoadBearing: no; ExtendToStructure: no; Reference: VIVES AVENTINO-R HUMO 29.3X29.3; ThermalTransmittance: 182.927 kg/K/s3
Pset_ManufacturerTypeInformation - Manufacturer: VIVES Azulejos y Gres S.A.

# IfcWallStandardCase: Muro básico:VIVES CAVOUR CEMENTO 30x30, Muro básico:VIVES CAVOUR CEMENTO 30x30:201430
In: FARNESE FLOOR TILES
Type - PredefinedType: STANDARD; Material: VIVES CAVOUR CEMENTO 30x30 0.0082 m
Pset_WallCommon - IsExternal: no; LoadBearing: no; ExtendToStructure: no; Reference: VIVES CAVOUR CEMENTO 30x30; ThermalTransmittance: 182.927 kg/K/s3
Pset_ManufacturerTypeInformation - Manufacturer: VIVES Azulejos y Gres S.A.

# IfcWallStandardCase: Muro básico:VIVES FARNESE CEMENTO 30x30, Muro básico:VIVES FARNESE CEMENTO 30x30:197381
In: FARNESE FLOOR TILES
Type - PredefinedType: STANDARD; Material: VIVES FARNESE CEMENTO 30x30 0.0082 m
Pset_WallCommon - IsExternal: no; LoadBearing: no; ExtendToStructure: no; Reference: VIVES FARNESE CEMENTO 30x30; ThermalTransmittance: 182.927 kg/K/s3
Pset_ManufacturerTypeInformation - Manufacturer: VIVES Azulejos y Gres S.A.

# IfcWallStandardCase: Muro básico:VIVES FARNESE CREMA 30x30, Muro básico:VIVES FARNESE CREMA 30x30:197760
In: FARNESE FLOOR TILES
Type - PredefinedType: STANDARD; Material: VIVES FARNESE CREMA 30x30 0.0082 m
Pset_WallCommon - IsExternal: no; LoadBearing: no; ExtendToStructure: no; Reference: VIVES FARNESE CREMA 30x30; ThermalTransmittance: 182.927 kg/K/s3
Pset_ManufacturerTypeInformation - Manufacturer: VIVES Azulejos y Gres S.A.

# IfcWallStandardCase: Muro básico:VIVES FARNESE GRAFITO 30x30, Muro básico:VIVES FARNESE GRAFITO 30x30:197888
In: FARNESE FLOOR TILES
Type - PredefinedType: STANDARD; Material: VIVES FARNESE GRAFITO 30x30 0.0082 m
Pset_WallCommon - IsExternal: no; LoadBearing: no; ExtendToStructure: no; Reference: VIVES FARNESE GRAFITO 30x30; ThermalTransmittance: 182.927 kg/K/s3
Pset_ManufacturerTypeInformation - Manufacturer: VIVES Azulejos y Gres S.A.

# IfcWallStandardCase: Muro básico:VIVES FARNESE HUMO 30x30, Muro básico:VIVES FARNESE HUMO 30x30:190692
In: FARNESE FLOOR TILES
Type - PredefinedType: STANDARD; Material: VIVES FARNESE HUMO 30x30 0.0082 m
Pset_WallCommon - Reference: VIVES FARNESE HUMO 30x30; IsExternal: no; LoadBearing: no; ExtendToStructure: no; ThermalTransmittance: 182.927 kg/K/s3
Pset_ManufacturerTypeInformation - Manufacturer: VIVES Azulejos y Gres S.A.

# IfcWallStandardCase: Muro básico:VIVES FARNESE-R CEMENTO 29.3X29.3 2, Muro básico:VIVES FARNESE-R CEMENTO 29.3X29.3 2:202318
In: FARNESE FLOOR TILES
Type - PredefinedType: STANDARD; Material: VIVES FARNESE-R CEMENTO 29.3x29.3 0.0082 m
Pset_WallCommon - IsExternal: no; LoadBearing: no; ExtendToStructure: no; Reference: VIVES FARNESE-R CEMENTO 29.3X29.3 2; ThermalTransmittance: 182.927 kg/K/s3
Pset_ManufacturerTypeInformation - Manufacturer: VIVES Azulejos y Gres S.A.

# IfcWallStandardCase: Muro básico:VIVES FARNESE-R CREMA 29.3X29.3, Muro básico:VIVES FARNESE-R CREMA 29.3X29.3:202414
In: FARNESE FLOOR TILES
Type - PredefinedType: STANDARD; Material: VIVES FARNESE-R CREMA 29.3x29.3 0.0082 m
Pset_WallCommon - IsExternal: no; LoadBearing: no; ExtendToStructure: no; Reference: VIVES FARNESE-R CREMA 29.3X29.3; ThermalTransmittance: 182.927 kg/K/s3
Pset_ManufacturerTypeInformation - Manufacturer: VIVES Azulejos y Gres S.A.

# IfcWallStandardCase: Muro básico:VIVES FARNESE-R GRAFITO 29.3X29.3, Muro básico:VIVES FARNESE-R GRAFITO 29.3X29.3:202512
In: FARNESE FLOOR TILES
Type - PredefinedType: STANDARD; Material: VIVES FARNESE-R GRAFITO 29.3x29.3 0.0082 m
Pset_WallCommon - IsExternal: no; LoadBearing: no; ExtendToStructure: no; Reference: VIVES FARNESE-R GRAFITO 29.3X29.3; ThermalTransmittance: 182.927 kg/K/s3
Pset_ManufacturerTypeInformation - Manufacturer: VIVES Azulejos y Gres S.A.

# IfcWallStandardCase: Muro básico:VIVES FARNESE-R HUMO 29.3X29.3, Muro básico:VIVES FARNESE-R HUMO 29.3X29.3:201997
In: FARNESE FLOOR TILES
Type - PredefinedType: STANDARD; Material: VIVES FARNESE-R HUMO 29.3x29.3 0.0082 m
Pset_WallCommon - IsExternal: no; LoadBearing: no; ExtendToStructure: no; Reference: VIVES FARNESE-R HUMO 29.3X29.3; ThermalTransmittance: 182.927 kg/K/s3
Pset_ManufacturerTypeInformation - Manufacturer: VIVES Azulejos y Gres S.A.

# IfcWallStandardCase: Muro básico:VIVES GADNER CEMENTO 30x30, Muro básico:VIVES GADNER CEMENTO 30x30:201478
In: FARNESE FLOOR TILES
Type - PredefinedType: STANDARD; Material: VIVES GADNER CEMENTO 30x30 0.0082 m
Pset_WallCommon - IsExternal: no; LoadBearing: no; ExtendToStructure: no; Reference: VIVES GADNER CEMENTO 30x30; ThermalTransmittance: 182.927 kg/K/s3
Pset_ManufacturerTypeInformation - Manufacturer: VIVES Azulejos y Gres S.A.

# IfcWallStandardCase: Muro básico:VIVES GADNER CREMA 30x30, Muro básico:VIVES GADNER CREMA 30x30:201462
In: FARNESE FLOOR TILES
Type - PredefinedType: STANDARD; Material: VIVES GADNER CREMA 30x30 0.0082 m
Pset_WallCommon - IsExternal: no; LoadBearing: no; ExtendToStructure: no; Reference: VIVES GADNER CREMA 30x30; ThermalTransmittance: 182.927 kg/K/s3
Pset_ManufacturerTypeInformation - Manufacturer: VIVES Azulejos y Gres S.A.

# IfcWallStandardCase: Muro básico:VIVES MANCINI AZUL 30x30, Muro básico:VIVES MANCINI AZUL 30x30:200571
In: FARNESE FLOOR TILES
Type - PredefinedType: STANDARD; Material: VIVES MANCINI AZUL 30x30 0.0082 m
Pset_WallCommon - IsExternal: no; LoadBearing: no; ExtendToStructure: no; Reference: VIVES MANCINI AZUL 30x30; ThermalTransmittance: 182.927 kg/K/s3
Pset_ManufacturerTypeInformation - Manufacturer: VIVES Azulejos y Gres S.A.

# IfcWallStandardCase: Muro básico:VIVES MANCINI BEIGE 30x30, Muro básico:VIVES MANCINI BEIGE 30x30:200603
In: FARNESE FLOOR TILES
Type - PredefinedType: STANDARD; Material: VIVES MANCINI BEIGE 30x30 0.0082 m
Pset_WallCommon - IsExternal: no; LoadBearing: no; ExtendToStructure: no; Reference: VIVES MANCINI BEIGE 30x30; ThermalTransmittance: 182.927 kg/K/s3
Pset_ManufacturerTypeInformation - Manufacturer: VIVES Azulejos y Gres S.A.

# IfcWallStandardCase: Muro básico:VIVES MANCINI CREMA 30x30, Muro básico:VIVES MANCINI CREMA 30x30:199100
In: FARNESE FLOOR TILES
Type - PredefinedType: STANDARD; Material: VIVES MANCINI CREMA 30x30 0.0082 m
Pset_WallCommon - IsExternal: no; LoadBearing: no; ExtendToStructure: no; Reference: VIVES MANCINI CREMA 30x30; ThermalTransmittance: 182.927 kg/K/s3
Pset_ManufacturerTypeInformation - Manufacturer: VIVES Azulejos y Gres S.A.

# IfcWallStandardCase: Muro básico:VIVES MANCINI GRAFITO 30x30, Muro básico:VIVES MANCINI GRAFITO 30x30:199116
In: FARNESE FLOOR TILES
Type - PredefinedType: STANDARD; Material: VIVES MANCINI GRAFITO 30x30 0.0082 m
Pset_WallCommon - IsExternal: no; LoadBearing: no; ExtendToStructure: no; Reference: VIVES MANCINI GRAFITO 30x30; ThermalTransmittance: 182.927 kg/K/s3
Pset_ManufacturerTypeInformation - Manufacturer: VIVES Azulejos y Gres S.A.

# IfcWallStandardCase: Muro básico:VIVES MANCINI HUMO 30x30, Muro básico:VIVES MANCINI HUMO 30x30:199068
In: FARNESE FLOOR TILES
Type - PredefinedType: STANDARD; Material: VIVES MANCINI HUMO 30x30 0.0082 m
Pset_WallCommon - IsExternal: no; LoadBearing: no; ExtendToStructure: no; Reference: VIVES MANCINI HUMO 30x30; ThermalTransmittance: 182.927 kg/K/s3
Pset_ManufacturerTypeInformation - Manufacturer: VIVES Azulejos y Gres S.A.

# IfcWallStandardCase: Muro básico:VIVES MANCINI ROSA 30x30, Muro básico:VIVES MANCINI ROSA 30x30:200619
In: FARNESE FLOOR TILES
Type - PredefinedType: STANDARD; Material: VIVES MANCINI ROSA 30x30 0.0082 m
Pset_WallCommon - IsExternal: no; LoadBearing: no; ExtendToStructure: no; Reference: VIVES MANCINI ROSA 30x30; ThermalTransmittance: 182.927 kg/K/s3
Pset_ManufacturerTypeInformation - Manufacturer: VIVES Azulejos y Gres S.A.

# IfcWallStandardCase: Muro básico:VIVES MOLISE-R CREMA 29.3X29.3, Muro básico:VIVES MOLISE-R CREMA 29.3X29.3:203814
In: FARNESE FLOOR TILES
Type - PredefinedType: STANDARD; Material: VIVES MOLISE-R CREMA 29.3x29.3 0.0082 m
Pset_WallCommon - IsExternal: no; LoadBearing: no; ExtendToStructure: no; Reference: VIVES MOLISE-R CREMA 29.3X29.3; ThermalTransmittance: 182.927 kg/K/s3
Pset_ManufacturerTypeInformation - Manufacturer: VIVES Azulejos y Gres S.A.

# IfcWallStandardCase: Muro básico:VIVES MOLISE-R GRAFITO 29.3X29.3, Muro básico:VIVES MOLISE-R GRAFITO 29.3X29.3:203830
In: FARNESE FLOOR TILES
Type - PredefinedType: STANDARD; Material: VIVES MOLISE-R GRAFITO 29.3x29.3 0.0082 m
Pset_WallCommon - IsExternal: no; LoadBearing: no; ExtendToStructure: no; Reference: VIVES MOLISE-R GRAFITO 29.3X29.3; ThermalTransmittance: 182.927 kg/K/s3
Pset_ManufacturerTypeInformation - Manufacturer: VIVES Azulejos y Gres S.A.

# IfcWallStandardCase: Muro básico:VIVES QUIRINALE-R MULTICOLOR 29.3X29.3, Muro básico:VIVES QUIRINALE-R MULTICOLOR 29.3X29.3:203419
In: FARNESE FLOOR TILES
Type - PredefinedType: STANDARD; Material: VIVES QUIRINALE-R MULTICOLOR 29.3x29.3 0.0082 m
Pset_WallCommon - IsExternal: no; LoadBearing: no; ExtendToStructure: no; Reference: VIVES QUIRINALE-R MULTICOLOR 29.3X29.3; ThermalTransmittance: 182.927 kg/K/s3
Pset_ManufacturerTypeInformation - Manufacturer: VIVES Azulejos y Gres S.A.
